VERSION 5.7 ;
  NOWIREEXTENSIONATPIN ON ;
  DIVIDERCHAR "/" ;
  BUSBITCHARS "[]" ;
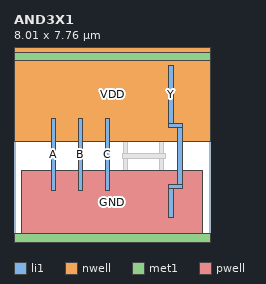
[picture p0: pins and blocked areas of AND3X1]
MACRO AND3X1
  CLASS CORE ;
  FOREIGN AND3X1 ;
  ORIGIN 0.000 0.000 ;
  SIZE 8.010 BY 7.760 ;
  SYMMETRY X Y ;
  SITE unitrh ;
  PIN Y
    DIRECTION OUTPUT ;
    USE SIGNAL ;
    ANTENNADIFFAREA 0.771900 ;
    PORT
      LAYER li1 ;
        RECT 6.330 4.845 6.500 7.200 ;
        RECT 6.330 4.675 6.865 4.845 ;
        RECT 6.695 2.345 6.865 4.675 ;
        RECT 6.325 2.175 6.865 2.345 ;
        RECT 6.325 1.020 6.495 2.175 ;
    END
  END Y
  PIN A
    DIRECTION INPUT ;
    USE SIGNAL ;
    ANTENNAGATEAREA 1.033250 ;
    PORT
      LAYER li1 ;
        RECT 1.515 2.095 1.685 5.045 ;
    END
  END A
  PIN B
    DIRECTION INPUT ;
    USE SIGNAL ;
    ANTENNAGATEAREA 1.014850 ;
    PORT
      LAYER li1 ;
        RECT 2.625 2.095 2.795 5.045 ;
    END
  END B
  PIN C
    DIRECTION INPUT ;
    USE SIGNAL ;
    ANTENNAGATEAREA 1.027250 ;
    PORT
      LAYER li1 ;
        RECT 3.735 2.095 3.905 5.045 ;
    END
  END C
  PIN VDD
    DIRECTION INOUT ;
    USE POWER ;
    SHAPE ABUTMENT ;
    PORT
      LAYER nwell ;
        RECT 0.000 4.110 8.010 7.940 ;
      LAYER met1 ;
        RECT 0.000 7.410 8.010 7.760 ;
    END
  END VDD
  PIN GND
    DIRECTION INOUT ;
    USE GROUND ;
    SHAPE ABUTMENT ;
    PORT
      LAYER pwell ;
        RECT 0.320 0.350 7.690 2.900 ;
        RECT 0.000 0.000 8.010 0.350 ;
      LAYER met1 ;
        RECT 0.000 0.000 8.010 0.350 ;
    END
  END GND
  OBS
      LAYER li1 ;
        RECT 0.000 7.410 8.010 7.760 ;
        RECT 0.320 4.290 0.660 7.410 ;
        RECT 1.495 5.395 1.665 7.410 ;
        RECT 1.935 5.420 2.105 7.200 ;
        RECT 2.375 5.735 2.545 7.410 ;
        RECT 2.815 5.420 2.985 7.200 ;
        RECT 3.255 5.735 3.425 7.410 ;
        RECT 3.695 5.420 3.865 7.200 ;
        RECT 4.135 5.735 4.305 7.410 ;
        RECT 1.935 5.250 4.645 5.420 ;
        RECT 0.320 0.350 0.660 2.900 ;
        RECT 0.995 1.855 1.165 1.935 ;
        RECT 1.965 1.855 2.135 1.935 ;
        RECT 2.935 1.855 3.105 1.935 ;
        RECT 0.995 1.685 3.105 1.855 ;
        RECT 0.995 0.555 1.165 1.685 ;
        RECT 1.480 0.350 1.650 1.310 ;
        RECT 1.965 0.805 2.135 1.685 ;
        RECT 2.935 1.605 3.105 1.685 ;
        RECT 2.455 1.260 2.625 1.340 ;
        RECT 3.505 1.260 3.675 1.935 ;
        RECT 4.475 1.930 4.645 5.250 ;
        RECT 5.130 4.290 5.470 7.410 ;
        RECT 5.890 5.365 6.060 7.410 ;
        RECT 6.770 5.365 6.940 7.410 ;
        RECT 2.455 1.090 3.675 1.260 ;
        RECT 2.455 1.010 2.625 1.090 ;
        RECT 2.935 0.805 3.105 0.885 ;
        RECT 1.965 0.635 3.105 0.805 ;
        RECT 1.965 0.555 2.135 0.635 ;
        RECT 2.935 0.555 3.105 0.635 ;
        RECT 3.505 0.805 3.675 1.090 ;
        RECT 3.990 1.760 4.645 1.930 ;
        RECT 3.990 1.025 4.160 1.760 ;
        RECT 4.475 0.805 4.645 1.575 ;
        RECT 3.505 0.635 4.645 0.805 ;
        RECT 3.505 0.555 3.675 0.635 ;
        RECT 4.475 0.555 4.645 0.635 ;
        RECT 5.130 0.350 5.470 2.900 ;
        RECT 5.955 2.100 6.125 5.045 ;
        RECT 7.350 4.290 7.690 7.410 ;
        RECT 5.845 0.800 6.015 1.930 ;
        RECT 6.815 0.800 6.985 1.930 ;
        RECT 5.845 0.630 6.985 0.800 ;
        RECT 5.845 0.350 6.015 0.630 ;
        RECT 6.330 0.350 6.500 0.630 ;
        RECT 6.815 0.350 6.985 0.630 ;
        RECT 7.350 0.350 7.690 2.900 ;
        RECT 0.000 0.000 8.010 0.350 ;
      LAYER mcon ;
        RECT 0.775 7.495 0.945 7.665 ;
        RECT 1.145 7.495 1.315 7.665 ;
        RECT 1.515 7.495 1.685 7.665 ;
        RECT 1.885 7.495 2.055 7.665 ;
        RECT 2.255 7.495 2.425 7.665 ;
        RECT 2.625 7.495 2.795 7.665 ;
        RECT 2.995 7.495 3.165 7.665 ;
        RECT 3.365 7.495 3.535 7.665 ;
        RECT 3.735 7.495 3.905 7.665 ;
        RECT 4.105 7.495 4.275 7.665 ;
        RECT 4.475 7.495 4.645 7.665 ;
        RECT 4.845 7.495 5.015 7.665 ;
        RECT 5.585 7.495 5.755 7.665 ;
        RECT 5.955 7.495 6.125 7.665 ;
        RECT 6.325 7.495 6.495 7.665 ;
        RECT 6.695 7.495 6.865 7.665 ;
        RECT 7.065 7.495 7.235 7.665 ;
        RECT 4.475 3.425 4.645 3.595 ;
        RECT 5.955 3.425 6.125 3.595 ;
        RECT 0.775 0.095 0.945 0.265 ;
        RECT 1.145 0.095 1.315 0.265 ;
        RECT 1.515 0.095 1.685 0.265 ;
        RECT 1.885 0.095 2.055 0.265 ;
        RECT 2.255 0.095 2.425 0.265 ;
        RECT 2.625 0.095 2.795 0.265 ;
        RECT 2.995 0.095 3.165 0.265 ;
        RECT 3.365 0.095 3.535 0.265 ;
        RECT 3.735 0.095 3.905 0.265 ;
        RECT 4.105 0.095 4.275 0.265 ;
        RECT 4.475 0.095 4.645 0.265 ;
        RECT 4.845 0.095 5.015 0.265 ;
        RECT 5.585 0.095 5.755 0.265 ;
        RECT 5.955 0.095 6.125 0.265 ;
        RECT 6.325 0.095 6.495 0.265 ;
        RECT 6.695 0.095 6.865 0.265 ;
        RECT 7.065 0.095 7.235 0.265 ;
      LAYER met1 ;
        RECT 4.445 3.595 4.675 3.625 ;
        RECT 5.925 3.595 6.155 3.625 ;
        RECT 4.415 3.425 6.185 3.595 ;
        RECT 4.445 3.395 4.675 3.425 ;
        RECT 5.925 3.395 6.155 3.425 ;
  END
END AND3X1
END LIBRARY

